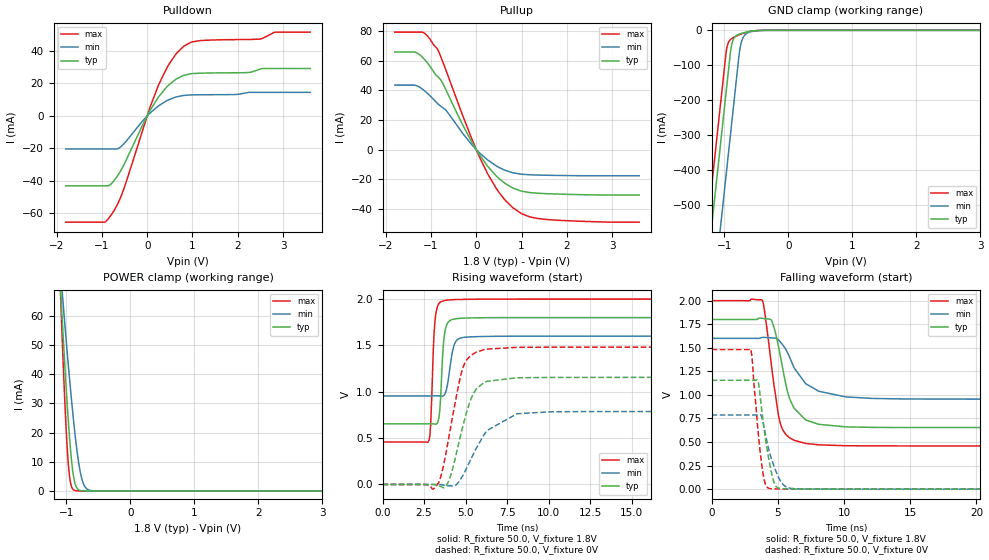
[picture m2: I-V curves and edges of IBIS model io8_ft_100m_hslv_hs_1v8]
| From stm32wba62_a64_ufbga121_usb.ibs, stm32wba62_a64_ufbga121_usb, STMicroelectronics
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[Model]   io8_ft_100m_hslv_hs_1v8
Model_type I/O
Polarity   Non-Inverting
Enable   Active-Low
| CAP_THRESHOLD on pad IOFT is "UDTCAPC" :
| Rising=30.0% of vddiom   Falling=70.0% of vddiom
| C_comp min and max val. don't necessarily correlate with the min and max pvt
| but are the smallest and greatest pad capacitance found.
| var   typ   min   max
C_comp   3.45872pF  3.43507pF  3.59281pF
|C_comp_pullup   2.05788pF  1.95427pF  2.20521pF
|C_comp_pulldown   1.40085pF  1.48081pF  1.38760pF
Vinl = 800.0mV
Vinh = 1.0V
Vmeas = 900.0mV   | Reference voltage for timing measurements
Cref  = 50.0pF   | Timing specification test load capacitance value
Rref  = 1.0MOhm   | Timing specification test load resistance value
Vref  = 990.0mV   | Timing specification test load voltage
[Model Spec]
| TIME_THRESHOLD on pin ZIV11 is "CMOS" :
| Rising=50.0% of vdd   Falling=50.0% of vdd
Vinl 702.50000mV 626.50000mV 788.50000mV
Vinh 1.09050V 959.50000mV 1.19650V
| variable   typ   min   max
[Temperature Range] 25.0 140.0 -40.0
| variable   typ   min   max
[Voltage Range] 1.8V 1.6V 2.0V
| variable   typ   min   max
[POWER Clamp Reference] 1.8V 1.6V 2.0V
| variable   typ   min   max
[GND Clamp Reference] 0V 0V 0V
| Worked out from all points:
|   slope of the pulldown table from 0 to 0.27 V, typ, clamps not added: 21.9 ohm
|   slope of the pullup table from 0 to 0.27 V, typ, clamps not added: 22.7 ohm
|   GND clamp passes 1 mA (typ) near -0.51 V on its own axis
|   POWER clamp passes 1 mA (typ) near -0.83 V on its own axis
|   rising waveform, R_fixture 50.0, V_fixture 1.8V: 20-80 % time 217ps typ, 343ps min, 202ps max; typ from 0.654 V to 1.8 V
|   falling waveform, R_fixture 50.0, V_fixture 1.8V: 20-80 % time 1.19ns typ, 1.89ns min, 886ps max; typ from 1.8 V to 0.654 V
|   rising waveform, R_fixture 50.0, V_fixture 0V: 20-80 % time 1.03ns typ, 1.75ns min, 947ps max; typ from 0 V to 1.16 V
|   falling waveform, R_fixture 50.0, V_fixture 0V: 20-80 % time 726ps typ, 952ps min, 588ps max; typ from 1.16 V to 0 V
[POWER Clamp]
-1.8V     396.4mA    285.5mA    556.9mA
-1.09V    69.42mA    75.17mA    67.14mA
-1.08V    65.31mA    72.42mA    61.23mA
-1.06V    57.23mA    66.98mA    49.77mA
-1.02V    41.75mA    56.3mA     28.91mA
-980mV    27.6mA     45.97mA    12.6mA
-940mV    15.59mA    36.11mA    3.485mA
-880mV    4.091mA    22.61mA    262.5uA
-820mV    594.6uA    11.56mA    16.39uA
-760mV    69.41uA    4.321mA    1.008uA
-630mV    611.2nA    197uA      2.478nA
3.6V      0A         0A         0A
[GND Clamp]
-1.8V     -1.583A    -1.82A     -1.468A
-1.43V    -953.9mA   -1.191A    -839.3mA
-1.24V    -630.9mA   -867.8mA   -516.3mA
-1.05V    -307.9mA   -544.8mA   -193.3mA
-980mV    -188.9mA   -425.8mA   -74.3mA
-950mV    -137.9mA   -374.8mA   -41.62mA
-890mV    -44.57mA   -272.8mA   -24.11mA
-800mV    -13.55mA   -119.8mA   -15.31mA
-760mV    -10.3mA    -56.67mA   -12.19mA
-720mV    -7.957mA   -26.08mA   -9.381mA
-540mV    -1.564mA   -2.435mA   -1.367mA
3.6V      1.279nA    269.1nA    528.1pA
| variable   typ   min   max
[Pullup Reference] 1.8V 1.6V 2.0V
| variable   typ   min   max
[Pulldown Reference] 0V 0V 0V
[Pullup]
-1.8V     66.02mA    43.62mA    79.48mA
-1.3V     65.22mA    42.98mA    79.48mA
-1.13V    60.52mA    39.44mA    78.38mA
-860mV    49.51mA    31.33mA    68.19mA
-760mV    45.99mA    28.84mA    60.97mA
-310mV    17.32mA    11.41mA    23.88mA
70mV      -3.436mA   -2.157mA   -4.962mA
440mV     -17.8mA    -11.01mA   -26.16mA
810mV     -26.07mA   -15.71mA   -39.4mA
1V        -28.15mA   -16.69mA   -43.34mA
1.37V     -29.57mA   -17.25mA   -46.68mA
3.6V      -30.74mA   -17.73mA   -49.13mA
[Pulldown]
-1.8V     -42.97mA   -20.34mA   -65.35mA
-940mV    -42.97mA   -20.34mA   -65.31mA
-780mV    -41.3mA    -20.34mA   -60.25mA
-530mV    -30.86mA   -17.55mA   -45.89mA
0V        -2fA       -570fA     -3.81fA
250mV     11.67mA    6.208mA    19.03mA
460mV     18.64mA    9.755mA    30.89mA
810mV     24.97mA    12.61mA    42.87mA
1.18V     26.28mA    13mA       46.33mA
2.49V     28.73mA    14.48mA    47.25mA
2.83V     29.16mA    14.48mA    51.53mA
3.6V      29.16mA    14.48mA    51.53mA
[Ramp]
dV/dt_r 693.11099mV/1.0245ns 472.15149mV/1.51156ns 888.79144mV/946.59581ps
dV/dt_f 687.69255mV/1.18433ns 386.84156mV/1.79429ns 924.86457mV/883.35799ps
R_load = 50.0
| Removed startup time: 0s 0s 0s  .
| Removed end time: 36.25ns.
[Rising Waveform]
R_fixture   = 50.0
V_fixture   = 1.8V
V_fixture_min = 1.6V
V_fixture_max = 2.0V
0s        653.8mV    955.3mV    458.6mV
2.8ns     653.9mV    955.4mV    476.4mV
2.9ns     654.2mV    955.4mV    646.7mV
3.05ns    654.3mV    955.6mV    1.413V
3.15ns    652.5mV    955.9mV    1.747V
3.45ns    801.9mV    955.3mV    1.963V
3.7ns     1.576V     961.4mV    1.982V
4.3ns     1.784V     1.496V     1.994V
4.95ns    1.794V     1.588V     1.997V
36.25ns   1.8V       1.6V       2V
| Removed startup time: 0s 0s 0s  .
| Removed end time: 99.25ns.
[Falling Waveform]
R_fixture   = 50.0
V_fixture   = 1.8V
V_fixture_min = 1.6V
V_fixture_max = 2.0V
0s        1.8V       1.6V       2V
3.85ns    1.812V     1.61V      1.997V
4.1ns     1.807V     1.609V     1.79V
4.55ns    1.782V     1.605V     1.281V
5.2ns     1.407V     1.56V      693.7mV
5.95ns    941.5mV    1.381V     540.2mV
7.1ns     734.3mV    1.12V      485.2mV
10.15ns   660.9mV    978.4mV    460.8mV
14.2ns    654.2mV    957.7mV    458.7mV
99.25ns   653.8mV    955.3mV    458.6mV
| Removed startup time: 0s 0s 0s  .
| Removed end time: 99.2ns.
[Rising Waveform]
R_fixture   = 50.0
V_fixture   = 0V
V_fixture_min = 0V
V_fixture_max = 0V
0s        4.616nV    149.8nV    3.36nV
3.3ns     -11mV      -64.4uV    -1.485mV
3.6ns     -29.18mV   -4.206mV   146.5mV
4ns       43.68mV    -14.62mV   513.9mV
4.85ns    636.5mV    101.4mV    1.263V
5.5ns     988.8mV    338.8mV    1.412V
6.3ns     1.113V     582.7mV    1.46V
8.1ns     1.151V     763.2mV    1.479V
10.15ns   1.155V     784.1mV    1.481V
99.2ns    1.155V     786.9mV    1.481V
| Removed startup time: 0s 0s 0s  .
| Removed end time: 36.25ns.
[Falling Waveform]
R_fixture   = 50.0
V_fixture   = 0V
V_fixture_min = 0V
V_fixture_max = 0V
0s        1.155V     786.9mV    1.481V
2.95ns    1.155V     787mV      1.485V
3.05ns    1.155V     787.1mV    1.403V
3.5ns     1.152V     788.7mV    631.9mV
3.8ns     825.6mV    758.2mV    249mV
4.05ns    548.6mV    596mV      60.83mV
4.35ns    298.8mV    404.3mV    8.598mV
4.85ns    32.45mV    193.9mV    2.677mV
5.95ns    2.427mV    8.508mV    1.118mV
36.25ns   56.59nV    570.2nV    10.4nV
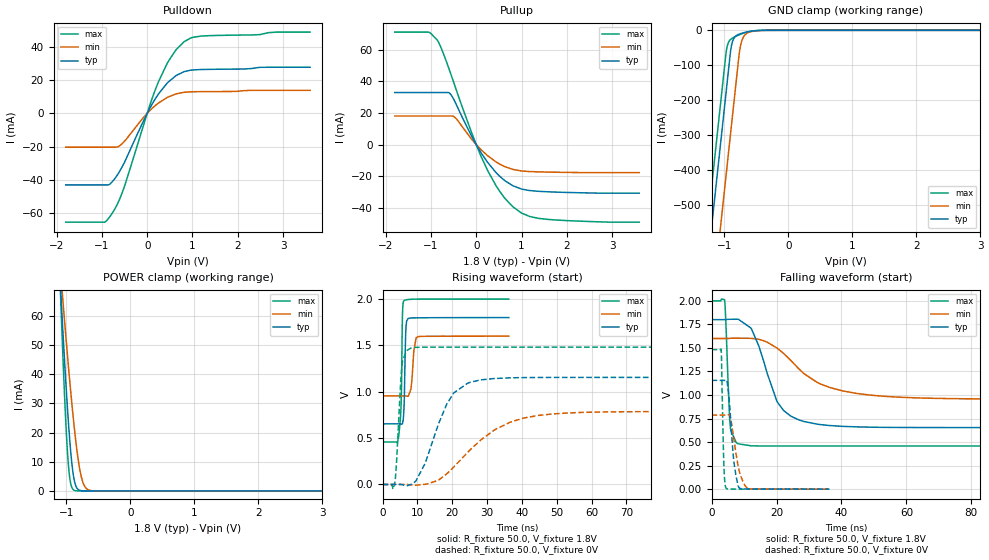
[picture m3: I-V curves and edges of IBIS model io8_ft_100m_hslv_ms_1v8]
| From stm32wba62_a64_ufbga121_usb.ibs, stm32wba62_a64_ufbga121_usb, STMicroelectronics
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[Model]   io8_ft_100m_hslv_ms_1v8
Model_type I/O
Polarity   Non-Inverting
Enable   Active-Low
| CAP_THRESHOLD on pad IOFT is "UDTCAPC" :
| Rising=30.0% of vddiom   Falling=70.0% of vddiom
| C_comp min and max val. don't necessarily correlate with the min and max pvt
| but are the smallest and greatest pad capacitance found.
| var   typ   min   max
C_comp   3.45864pF  3.43495pF  3.62425pF
|C_comp_pullup   2.05752pF  1.95381pF  2.23556pF
|C_comp_pulldown   1.40113pF  1.48114pF  1.38868pF
Vinl = 800.0mV
Vinh = 1.0V
Vmeas = 900.0mV   | Reference voltage for timing measurements
Cref  = 50.0pF   | Timing specification test load capacitance value
Rref  = 1.0MOhm   | Timing specification test load resistance value
Vref  = 990.0mV   | Timing specification test load voltage
[Model Spec]
| TIME_THRESHOLD on pin ZIV11 is "CMOS" :
| Rising=50.0% of vdd   Falling=50.0% of vdd
Vinl 702.50000mV 626.50000mV 788.50000mV
Vinh 1.09050V 959.50000mV 1.19650V
| variable   typ   min   max
[Temperature Range] 25.0 140.0 -40.0
| variable   typ   min   max
[Voltage Range] 1.8V 1.6V 2.0V
| variable   typ   min   max
[POWER Clamp Reference] 1.8V 1.6V 2.0V
| variable   typ   min   max
[GND Clamp Reference] 0V 0V 0V
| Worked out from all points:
|   slope of the pulldown table from 0 to 0.27 V, typ, clamps not added: 21.9 ohm
|   slope of the pullup table from 0 to 0.27 V, typ, clamps not added: 22.7 ohm
|   GND clamp passes 1 mA (typ) near -0.51 V on its own axis
|   POWER clamp passes 1 mA (typ) near -0.83 V on its own axis
|   rising waveform, R_fixture 50.0, V_fixture 1.8V: 20-80 % time 385ps typ, 810ps min, 429ps max; typ from 0.654 V to 1.8 V
|   falling waveform, R_fixture 50.0, V_fixture 1.8V: 20-80 % time 7.24ns typ, 14.9ns min, 1.05ns max; typ from 1.8 V to 0.654 V
|   rising waveform, R_fixture 50.0, V_fixture 0V: 20-80 % time 7.14ns typ, 14.7ns min, 1.26ns max; typ from 0 V to 1.16 V
|   falling waveform, R_fixture 50.0, V_fixture 0V: 20-80 % time 1.63ns typ, 2.37ns min, 590ps max; typ from 1.16 V to 0 V
[POWER Clamp]
-1.8V     396.4mA    285.5mA    556.9mA
-1.09V    69.42mA    75.17mA    67.14mA
-1.08V    65.31mA    72.42mA    61.23mA
-1.06V    57.23mA    66.98mA    49.77mA
-1.02V    41.75mA    56.3mA     28.91mA
-980mV    27.6mA     45.97mA    12.6mA
-940mV    15.59mA    36.11mA    3.485mA
-880mV    4.091mA    22.61mA    262.5uA
-820mV    594.6uA    11.56mA    16.39uA
-760mV    69.41uA    4.321mA    1.008uA
-630mV    611.3nA    197uA      2.478nA
3.6V      0A         0A         0A
[GND Clamp]
-1.8V     -1.583A    -1.82A     -1.468A
-1.43V    -953.9mA   -1.191A    -839.3mA
-1.24V    -630.9mA   -867.8mA   -516.3mA
-1.05V    -307.9mA   -544.8mA   -193.3mA
-980mV    -188.9mA   -425.8mA   -74.3mA
-950mV    -137.9mA   -374.8mA   -41.62mA
-890mV    -44.57mA   -272.8mA   -24.11mA
-800mV    -13.55mA   -119.8mA   -15.31mA
-760mV    -10.3mA    -56.67mA   -12.19mA
-720mV    -7.957mA   -26.08mA   -9.381mA
-540mV    -1.564mA   -2.435mA   -1.367mA
3.6V      1.279nA    269.1nA    528.1pA
| variable   typ   min   max
[Pullup Reference] 1.8V 1.6V 2.0V
| variable   typ   min   max
[Pulldown Reference] 0V 0V 0V
[Pullup]
-1.8V     33mA       18.15mA    71.29mA
-1.06V    33mA       18.15mA    71.26mA
-860mV    33mA       18.15mA    66.24mA
-560mV    31.64mA    18.15mA    44.58mA
-440mV    25.34mA    16.38mA    34.57mA
-120mV    6.338mA    4.065mA    8.965mA
110mV     -5.296mA   -3.32mA    -7.658mA
440mV     -17.8mA    -11.01mA   -26.16mA
810mV     -26.07mA   -15.71mA   -39.4mA
1V        -28.15mA   -16.69mA   -43.34mA
1.37V     -29.57mA   -17.25mA   -46.68mA
3.6V      -30.74mA   -17.73mA   -49.13mA
[Pulldown]
-1.8V     -42.97mA   -20.34mA   -65.35mA
-940mV    -42.97mA   -20.34mA   -65.31mA
-780mV    -41.3mA    -20.34mA   -60.25mA
-650mV    -36.58mA   -20.1mA    -53.93mA
-530mV    -30.86mA   -17.55mA   -45.89mA
0V        2.4fA      -230fA     0A
250mV     11.67mA    6.208mA    19.03mA
460mV     18.64mA    9.755mA    30.89mA
630mV     22.5mA     11.58mA    37.88mA
810mV     24.97mA    12.61mA    42.87mA
1.18V     26.28mA    13mA       46.33mA
3.6V      27.66mA    13.8mA     48.75mA
[Ramp]
dV/dt_r 693.10101mV/7.01092ns 472.10736mV/14.47133ns 888.7928mV/1.25662ns
dV/dt_f 687.69291mV/7.00172ns 386.8437mV/14.79899ns 924.86462mV/1.05074ns
R_load = 50.0
| Removed startup time: 0s 0s 0s  .
| Removed end time: 36.25ns.
[Rising Waveform]
R_fixture   = 50.0
V_fixture   = 1.8V
V_fixture_min = 1.6V
V_fixture_max = 2.0V
0s        653.8mV    955.3mV    458.6mV
4.65ns    653.9mV    955.3mV    522.8mV
5.3ns     651.8mV    955.3mV    838.2mV
5.7ns     657.4mV    955.3mV    1.8V
6.1ns     781.3mV    955.3mV    1.98V
6.7ns     1.674V     954.6mV    1.991V
7.35ns    1.79V      951.2mV    1.995V
8.15ns    1.796V     1.029V     1.997V
9.65ns    1.797V     1.584V     1.999V
36.25ns   1.8V       1.6V       2V
| Removed startup time: 0s 0s 0s  .
| Removed end time: 199.25ns.
[Falling Waveform]
R_fixture   = 50.0
V_fixture   = 1.8V
V_fixture_min = 1.6V
V_fixture_max = 2.0V
0s        1.8V       1.6V       2V
4.05ns    1.8V       1.6V       2.003V
5.7ns     1.804V     1.602V     690.4mV
8.2ns     1.805V     1.603V     481.4mV
12.2ns    1.709V     1.602V     460.2mV
20.05ns   940.3mV    1.501V     458.6mV
22.2ns    834.7mV    1.441V     458.6mV
32.55ns   689.9mV    1.133V     458.6mV
65.1ns    654.5mV    967.3mV    458.6mV
199.3ns   653.8mV    955.3mV    458.6mV
| Removed startup time: 0s 0s 0s  .
| Removed end time: 199.2ns.
[Rising Waveform]
R_fixture   = 50.0
V_fixture   = 0V
V_fixture_min = 0V
V_fixture_max = 0V
0s        4.612nV    149.7nV    3.102nV
3.45ns    3.66uV     3.237uV    7.375mV
3.95ns    1.413uV    2.741uV    200.7mV
5.6ns     -1.633mV   101.6nV    1.29V
8.15ns    52.07uV    -4.203mV   1.472V
12.2ns    225.7mV    1.966mV    1.481V
20.35ns   982.5mV    184.4mV    1.481V
28.45ns   1.129V     487mV      1.481V
52.85ns   1.155V     770.7mV    1.481V
199.2ns   1.155V     786.8mV    1.481V
| Removed startup time: 0s 0s 0s  .
| Removed end time: 36.25ns.
[Falling Waveform]
R_fixture   = 50.0
V_fixture   = 0V
V_fixture_min = 0V
V_fixture_max = 0V
0s        1.155V     786.9mV    1.481V
2.95ns    1.155V     786.9mV    1.485V
3.8ns     1.155V     786.9mV    251.4mV
4.05ns    1.155V     786.9mV    87.48mV
4.45ns    1.157V     786.9mV    11.74mV
5.2ns     1.03V      789.1mV    2.24mV
6.9ns     283.3mV    522.1mV    777.8uV
8.45ns    15.14mV    201.1mV    318.5uV
11.85ns   1.5mV      2.949mV    50.23uV
36.25ns   41.83uV    151.8uV    18.8nV
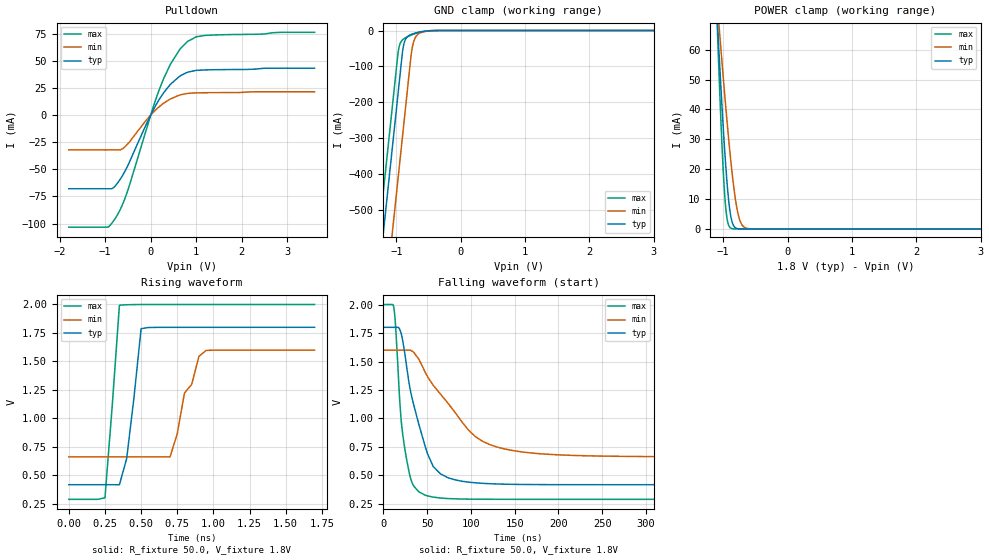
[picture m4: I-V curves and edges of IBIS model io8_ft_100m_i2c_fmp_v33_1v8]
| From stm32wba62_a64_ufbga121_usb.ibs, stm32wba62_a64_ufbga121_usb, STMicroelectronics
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[Model]   io8_ft_100m_i2c_fmp_v33_1v8
Model_type I/O_open_drain
Polarity   Non-Inverting
Enable   Active-Low
| CAP_THRESHOLD on pad IOFT is "UDTCAPC" :
| Rising=30.0% of vddiom   Falling=70.0% of vddiom
| C_comp min and max val. don't necessarily correlate with the min and max pvt
| but are the smallest and greatest pad capacitance found.
| var   typ   min   max
C_comp   3.34864pF  3.31909pF  3.48425pF
|C_comp_pulldown   3.34864pF  3.31909pF  3.48425pF
Vinl = 800.0mV
Vinh = 1.0V
Vmeas = 900.0mV   | Reference voltage for timing measurements
Cref  = 50.0pF   | Timing specification test load capacitance value
Rref  = 1.0MOhm   | Timing specification test load resistance value
Vref  = 990.0mV   | Timing specification test load voltage
[Model Spec]
| TIME_THRESHOLD on pin ZII2CV11 is "CMOS" :
| Rising=50.0% of vdd   Falling=50.0% of vdd
Vinl 697.50000mV 620.50000mV 783.50000mV
Vinh 1.08850V 957.50000mV 1.19550V
| variable   typ   min   max
[Temperature Range] 25.0 140.0 -40.0
| variable   typ   min   max
[Voltage Range] 1.8V 1.6V 2.0V
| variable   typ   min   max
[POWER Clamp Reference] 1.8V 1.6V 2.0V
| variable   typ   min   max
[GND Clamp Reference] 0V 0V 0V
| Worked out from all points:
|   slope of the pulldown table from 0 to 0.27 V, typ, clamps not added: 13.7 ohm
|   GND clamp passes 1 mA (typ) near -0.51 V on its own axis
|   POWER clamp passes 1 mA (typ) near -0.83 V on its own axis
|   rising waveform, R_fixture 50.0, V_fixture 1.8V: 20-80 % time 74ps typ, 127ps min, 60.6ps max; typ from 0.419 V to 1.8 V
|   falling waveform, R_fixture 50.0, V_fixture 1.8V: 20-80 % time 25ns typ, 56.4ns min, 11.6ns max; typ from 1.8 V to 0.419 V
[POWER Clamp]
-1.8V     396.4mA    285.5mA    556.9mA
-1.09V    69.42mA    75.17mA    67.14mA
-1.08V    65.31mA    72.42mA    61.23mA
-1.06V    57.23mA    66.98mA    49.77mA
-1.02V    41.75mA    56.3mA     28.91mA
-980mV    27.6mA     45.97mA    12.6mA
-940mV    15.59mA    36.11mA    3.485mA
-880mV    4.091mA    22.61mA    262.5uA
-820mV    594.6uA    11.56mA    16.39uA
-760mV    69.41uA    4.321mA    1.008uA
-630mV    611.2nA    197uA      2.486nA
3.6V      0A         0A         0A
[GND Clamp]
-1.8V     -1.583A    -1.82A     -1.468A
-1.43V    -953.9mA   -1.191A    -839.3mA
-1.24V    -630.9mA   -867.8mA   -516.3mA
-1.05V    -307.9mA   -544.8mA   -193.3mA
-980mV    -188.9mA   -425.8mA   -74.3mA
-950mV    -137.9mA   -374.8mA   -41.62mA
-890mV    -44.57mA   -272.8mA   -24.11mA
-800mV    -13.55mA   -119.8mA   -15.31mA
-760mV    -10.3mA    -56.67mA   -12.19mA
-720mV    -7.957mA   -26.08mA   -9.381mA
-540mV    -1.564mA   -2.435mA   -1.367mA
3.6V      1.281nA    268.1nA    531.2pA
| variable   typ   min   max
[Pullup Reference] 1.8V 1.6V 2.0V
| variable   typ   min   max
[Pulldown Reference] 0V 0V 0V
[Pulldown]
-1.8V     -67.91mA   -32.13mA   -103.3mA
-940mV    -67.91mA   -32.13mA   -103.2mA
-780mV    -65.26mA   -32.13mA   -95.24mA
-650mV    -57.81mA   -31.76mA   -85.25mA
-530mV    -48.77mA   -27.72mA   -72.55mA
0V        1fA        -20fA      -1.8fA
250mV     18.45mA    9.809mA    30.09mA
440mV     28.58mA    14.98mA    47.3mA
630mV     35.56mA    18.31mA    59.9mA
810mV     39.48mA    19.92mA    67.8mA
1.18V     41.55mA    20.55mA    73.29mA
3.6V      43.15mA    21.44mA    76.19mA
[Ramp]
dV/dt_r 828.62853mV/1.35705ns 561.62363mV/2.54413ns 1.02558V/770.99655ps
dV/dt_f 828.65502mV/24.91356ns 561.51224mV/56.08077ns 1.02559V/11.58574ns
R_load = 50.0
| Removed startup time: 0s 0s 0s  .
| Removed end time: 1.7ns.
[Rising Waveform]
R_fixture   = 50.0
V_fixture   = 1.8V
V_fixture_min = 1.6V
V_fixture_max = 2.0V
0s        418.9mV    663.9mV    290.7mV
250ps     418.9mV    663.9mV    303.9mV
350ps     418mV      663.9mV    1.994V
400ps     647.5mV    663.9mV    1.998V
500ps     1.788V     663.9mV    2V
700ps     1.8V       662.7mV    2V
750ps     1.8V       865.4mV    2V
800ps     1.8V       1.223V     2V
950ps     1.8V       1.597V     2V
1.7ns     1.8V       1.6V       2V
| Removed startup time: 0s 0s 0s  .
| Removed end time: 398.4ns.
[Falling Waveform]
R_fixture   = 50.0
V_fixture   = 1.8V
V_fixture_min = 1.6V
V_fixture_max = 2.0V
0s        1.8V       1.6V       2V
11.85ns   1.8V       1.6V       1.975V
22.1ns    1.683V     1.6V       859.3mV
31.35ns   1.228V     1.597V     467.6mV
40.65ns   944.5mV    1.518V     355.8mV
50.5ns    689.4mV    1.366V     320.8mV
65.05ns   515.3mV    1.216V     302.3mV
97.6ns    441.2mV    895.3mV    292.4mV
130.1ns   425.4mV    749mV      291mV
398.4ns   418.9mV    664.1mV    290.7mV
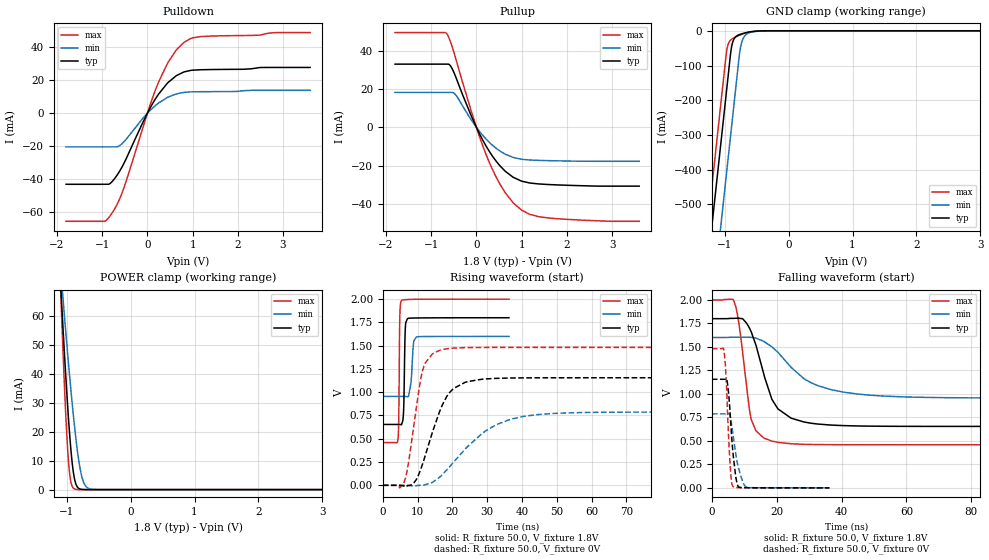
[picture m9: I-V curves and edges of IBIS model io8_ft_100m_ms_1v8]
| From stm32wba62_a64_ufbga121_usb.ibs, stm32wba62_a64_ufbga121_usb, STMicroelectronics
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[Model]   io8_ft_100m_ms_1v8
Model_type I/O
Polarity   Non-Inverting
Enable   Active-Low
| CAP_THRESHOLD on pad IOFT is "UDTCAPC" :
| Rising=30.0% of vddiom   Falling=70.0% of vddiom
| C_comp min and max val. don't necessarily correlate with the min and max pvt
| but are the smallest and greatest pad capacitance found.
| var   typ   min   max
C_comp   3.36302pF  3.33592pF  3.49657pF
|C_comp_pullup   1.98082pF  1.87509pF  2.12867pF
|C_comp_pulldown   1.38220pF  1.46083pF  1.36790pF
Vinl = 800.0mV
Vinh = 1.0V
Vmeas = 900.0mV   | Reference voltage for timing measurements
Cref  = 50.0pF   | Timing specification test load capacitance value
Rref  = 1.0MOhm   | Timing specification test load resistance value
Vref  = 990.0mV   | Timing specification test load voltage
[Model Spec]
| TIME_THRESHOLD on pin ZIV11 is "CMOS" :
| Rising=50.0% of vdd   Falling=50.0% of vdd
Vinl 702.50000mV 626.50000mV 788.50000mV
Vinh 1.09050V 959.50000mV 1.19650V
| variable   typ   min   max
[Temperature Range] 25.0 140.0 -40.0
| variable   typ   min   max
[Voltage Range] 1.8V 1.6V 2.0V
| variable   typ   min   max
[POWER Clamp Reference] 1.8V 1.6V 2.0V
| variable   typ   min   max
[GND Clamp Reference] 0V 0V 0V
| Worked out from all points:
|   slope of the pulldown table from 0 to 0.27 V, typ, clamps not added: 21.9 ohm
|   slope of the pullup table from 0 to 0.27 V, typ, clamps not added: 22.5 ohm
|   GND clamp passes 1 mA (typ) near -0.51 V on its own axis
|   POWER clamp passes 1 mA (typ) near -0.83 V on its own axis
|   rising waveform, R_fixture 50.0, V_fixture 1.8V: 20-80 % time 320ps typ, 666ps min, 236ps max; typ from 0.654 V to 1.8 V
|   falling waveform, R_fixture 50.0, V_fixture 1.8V: 20-80 % time 6.53ns typ, 13.6ns min, 3.34ns max; typ from 1.8 V to 0.654 V
|   rising waveform, R_fixture 50.0, V_fixture 0V: 20-80 % time 6.51ns typ, 13.4ns min, 3.54ns max; typ from 0 V to 1.16 V
|   falling waveform, R_fixture 50.0, V_fixture 0V: 20-80 % time 1.61ns typ, 2.38ns min, 1.18ns max; typ from 1.16 V to 0 V
[POWER Clamp]
-1.8V     396.4mA    285.5mA    556.9mA
-1.09V    69.42mA    75.17mA    67.14mA
-1.08V    65.31mA    72.42mA    61.23mA
-1.06V    57.23mA    66.98mA    49.77mA
-1.02V    41.75mA    56.3mA     28.91mA
-980mV    27.6mA     45.97mA    12.6mA
-940mV    15.59mA    36.11mA    3.485mA
-880mV    4.091mA    22.61mA    262.5uA
-820mV    594.6uA    11.56mA    16.39uA
-760mV    69.41uA    4.321mA    1.008uA
-630mV    611.2nA    197uA      2.486nA
3.6V      0A         0A         0A
[GND Clamp]
-1.8V     -1.583A    -1.82A     -1.468A
-1.43V    -953.9mA   -1.191A    -839.3mA
-1.24V    -630.9mA   -867.8mA   -516.3mA
-1.05V    -307.9mA   -544.8mA   -193.3mA
-980mV    -188.9mA   -425.8mA   -74.3mA
-950mV    -137.9mA   -374.8mA   -41.62mA
-890mV    -44.57mA   -272.8mA   -24.11mA
-800mV    -13.55mA   -119.8mA   -15.31mA
-760mV    -10.3mA    -56.67mA   -12.19mA
-720mV    -7.957mA   -26.08mA   -9.381mA
-540mV    -1.564mA   -2.435mA   -1.367mA
3.6V      1.281nA    268.1nA    531.2pA
| variable   typ   min   max
[Pullup Reference] 1.8V 1.6V 2.0V
| variable   typ   min   max
[Pulldown Reference] 0V 0V 0V
[Pullup]
-1.8V     33.1mA     18.3mA     49.62mA
-650mV    33.1mA     18.3mA     48.8mA
-570mV    32.05mA    18.3mA     44.54mA
-460mV    26.55mA    17.03mA    36.18mA
0V        593fA      222.5pA    3.42fA
280mV     -12.36mA   -7.702mA   -18.01mA
630mV     -22.78mA   -13.92mA   -33.91mA
810mV     -26.07mA   -15.71mA   -39.4mA
1V        -28.15mA   -16.69mA   -43.34mA
1.18V     -29.09mA   -17.06mA   -45.52mA
1.6V      -29.9mA    -17.4mA    -47.4mA
3.6V      -30.74mA   -17.73mA   -49.13mA
[Pulldown]
-1.8V     -42.97mA   -20.34mA   -65.35mA
-940mV    -42.97mA   -20.34mA   -65.31mA
-780mV    -41.3mA    -20.34mA   -60.25mA
-650mV    -36.58mA   -20.1mA    -53.93mA
-530mV    -30.86mA   -17.55mA   -45.89mA
0V        -1.6fA     0A         0A
250mV     11.67mA    6.208mA    19.03mA
460mV     18.64mA    9.755mA    30.89mA
630mV     22.5mA     11.58mA    37.88mA
810mV     24.97mA    12.61mA    42.87mA
1.18V     26.28mA    13mA       46.33mA
3.6V      27.68mA    13.83mA    48.76mA
[Ramp]
dV/dt_r 693.10628mV/6.46288ns 472.12859mV/13.31506ns 888.79178mV/3.53703ns
dV/dt_f 687.69291mV/6.33324ns 386.84616mV/13.42398ns 924.86465mV/3.34134ns
R_load = 50.0
| Removed startup time: 0s 0s 0s  .
| Removed end time: 36.25ns.
[Rising Waveform]
R_fixture   = 50.0
V_fixture   = 1.8V
V_fixture_min = 1.6V
V_fixture_max = 2.0V
0s        653.8mV    955.3mV    458.6mV
4.3ns     653.9mV    955.3mV    481.8mV
4.55ns    653.9mV    955.3mV    667.9mV
4.9ns     653.6mV    955.3mV    1.838V
5.35ns    650.2mV    955.3mV    1.985V
6ns       836.9mV    955.3mV    1.993V
6.5ns     1.712V     954.7mV    1.994V
7.1ns     1.791V     951.2mV    1.996V
9.65ns    1.797V     1.594V     1.998V
36.25ns   1.8V       1.6V       2V
| Removed startup time: 0s 0s 0s  .
| Removed end time: 199.25ns.
[Falling Waveform]
R_fixture   = 50.0
V_fixture   = 1.8V
V_fixture_min = 1.6V
V_fixture_max = 2.0V
0s        1.8V       1.6V       2V
6.75ns    1.803V     1.603V     1.993V
8.35ns    1.804V     1.602V     1.745V
12.2ns    1.653V     1.601V     721.7mV
13.6ns    1.518V     1.593V     606.6mV
18.5ns    942.5mV    1.5V       497.5mV
24.4ns    742.3mV    1.284V     469.2mV
30.65ns   687.3mV    1.117V     461.5mV
48.8ns    656.6mV    985.9mV    458.6mV
199.3ns   653.8mV    955.3mV    458.6mV
| Removed startup time: 0s 0s 0s  .
| Removed end time: 199.2ns.
[Rising Waveform]
R_fixture   = 50.0
V_fixture   = 0V
V_fixture_min = 0V
V_fixture_max = 0V
0s        4.66nV     149.2nV    3.397nV
6ns       -7.351mV   13.22uV    21.83mV
7.2ns     -3.754mV   -706.2uV   204.3mV
8.95ns    28.25mV    -10.05mV   653.6mV
11.45ns   232.8mV    1.899mV    1.236V
17.1ns    863.4mV    114.8mV    1.458V
20.35ns   1.041V     249.4mV    1.474V
29.7ns    1.143V     587.7mV    1.481V
44.75ns   1.155V     760.5mV    1.481V
199.2ns   1.155V     786.9mV    1.481V
| Removed startup time: 0s 0s 0s  .
| Removed end time: 36.25ns.
[Falling Waveform]
R_fixture   = 50.0
V_fixture   = 0V
V_fixture_min = 0V
V_fixture_max = 0V
0s        1.155V     786.9mV    1.481V
3.7ns     1.155V     786.9mV    1.461V
4.25ns    1.155V     786.9mV    1.258V
4.9ns     1.087V     787mV      741.7mV
5.75ns    731.2mV    742.4mV    181.1mV
6.05ns    572.3mV    680.9mV    67.91mV
6.4ns     412.7mV    597.5mV    19.68mV
7.8ns     38.95mV    274mV      3.09mV
10.35ns   2.119mV    12.81mV    775.3uV
36.25ns   30.42uV    125.9uV    3.735uV
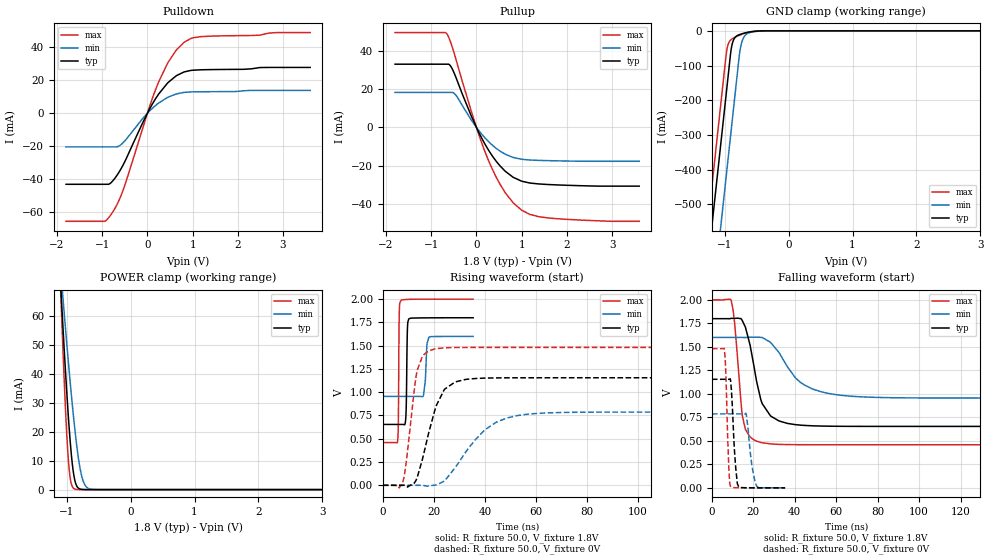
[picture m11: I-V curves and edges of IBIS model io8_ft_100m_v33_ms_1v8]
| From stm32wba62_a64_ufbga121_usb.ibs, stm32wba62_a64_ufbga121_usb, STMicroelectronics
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[Model]   io8_ft_100m_v33_ms_1v8
Model_type I/O
Polarity   Non-Inverting
Enable   Active-Low
| CAP_THRESHOLD on pad IOFT is "UDTCAPC" :
| Rising=30.0% of vddiom   Falling=70.0% of vddiom
| C_comp min and max val. don't necessarily correlate with the min and max pvt
| but are the smallest and greatest pad capacitance found.
| var   typ   min   max
C_comp   3.44267pF  3.41636pF  3.57935pF
|C_comp_pullup   2.04610pF  1.94135pF  2.19277pF
|C_comp_pulldown   1.39657pF  1.47502pF  1.38658pF
Vinl = 800.0mV
Vinh = 1.0V
Vmeas = 900.0mV   | Reference voltage for timing measurements
Cref  = 50.0pF   | Timing specification test load capacitance value
Rref  = 1.0MOhm   | Timing specification test load resistance value
Vref  = 990.0mV   | Timing specification test load voltage
[Model Spec]
| TIME_THRESHOLD on pin ZIV33M is "CMOS" :
| Rising=50.0% of vddiom   Falling=50.0% of vddiom
Vinl 697.50000mV 620.50000mV 783.50000mV
Vinh 1.08850V 957.50000mV 1.19550V
| variable   typ   min   max
[Temperature Range] 25.0 140.0 -40.0
| variable   typ   min   max
[Voltage Range] 1.8V 1.6V 2.0V
| variable   typ   min   max
[POWER Clamp Reference] 1.8V 1.6V 2.0V
| variable   typ   min   max
[GND Clamp Reference] 0V 0V 0V
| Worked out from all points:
|   slope of the pulldown table from 0 to 0.27 V, typ, clamps not added: 21.9 ohm
|   slope of the pullup table from 0 to 0.27 V, typ, clamps not added: 22.5 ohm
|   GND clamp passes 1 mA (typ) near -0.51 V on its own axis
|   POWER clamp passes 1 mA (typ) near -0.83 V on its own axis
|   rising waveform, R_fixture 50.0, V_fixture 1.8V: 20-80 % time 333ps typ, 735ps min, 241ps max; typ from 0.654 V to 1.8 V
|   falling waveform, R_fixture 50.0, V_fixture 1.8V: 20-80 % time 6.85ns typ, 14.4ns min, 3.5ns max; typ from 1.8 V to 0.654 V
|   rising waveform, R_fixture 50.0, V_fixture 0V: 20-80 % time 7.17ns typ, 14.4ns min, 3.76ns max; typ from 0 V to 1.16 V
|   falling waveform, R_fixture 50.0, V_fixture 0V: 20-80 % time 1.72ns typ, 2.52ns min, 1.25ns max; typ from 1.16 V to 0 V
[POWER Clamp]
-1.8V     396.4mA    285.5mA    556.9mA
-1.09V    69.42mA    75.17mA    67.14mA
-1.08V    65.31mA    72.42mA    61.23mA
-1.06V    57.23mA    66.98mA    49.77mA
-1.02V    41.75mA    56.3mA     28.91mA
-980mV    27.6mA     45.97mA    12.6mA
-940mV    15.59mA    36.11mA    3.485mA
-880mV    4.091mA    22.61mA    262.5uA
-820mV    594.6uA    11.56mA    16.39uA
-760mV    69.41uA    4.321mA    1.008uA
-630mV    611.2nA    197uA      2.486nA
3.6V      0A         0A         0A
[GND Clamp]
-1.8V     -1.583A    -1.82A     -1.468A
-1.43V    -953.9mA   -1.191A    -839.3mA
-1.24V    -630.9mA   -867.8mA   -516.3mA
-1.05V    -307.9mA   -544.8mA   -193.3mA
-980mV    -188.9mA   -425.8mA   -74.3mA
-950mV    -137.9mA   -374.8mA   -41.62mA
-890mV    -44.57mA   -272.8mA   -24.11mA
-800mV    -13.55mA   -119.8mA   -15.31mA
-760mV    -10.3mA    -56.67mA   -12.19mA
-720mV    -7.957mA   -26.08mA   -9.381mA
-540mV    -1.564mA   -2.435mA   -1.367mA
3.6V      1.281nA    268nA      531.2pA
| variable   typ   min   max
[Pullup Reference] 1.8V 1.6V 2.0V
| variable   typ   min   max
[Pulldown Reference] 0V 0V 0V
[Pullup]
-1.8V     33.11mA    18.3mA     49.64mA
-650mV    33.11mA    18.3mA     48.82mA
-570mV    32.06mA    18.3mA     44.54mA
-460mV    26.56mA    17.03mA    36.18mA
0V        593fA      222.5pA    3.42fA
280mV     -12.36mA   -7.702mA   -18.01mA
630mV     -22.78mA   -13.92mA   -33.91mA
810mV     -26.07mA   -15.71mA   -39.4mA
1V        -28.15mA   -16.69mA   -43.34mA
1.18V     -29.09mA   -17.06mA   -45.52mA
1.6V      -29.9mA    -17.4mA    -47.4mA
3.6V      -30.74mA   -17.73mA   -49.13mA
[Pulldown]
-1.8V     -42.97mA   -20.34mA   -65.35mA
-940mV    -42.97mA   -20.34mA   -65.31mA
-780mV    -41.3mA    -20.34mA   -60.25mA
-650mV    -36.58mA   -20.1mA    -53.93mA
-530mV    -30.86mA   -17.55mA   -45.89mA
0V        1fA        10fA       -3.6fA
250mV     11.67mA    6.208mA    19.03mA
460mV     18.64mA    9.755mA    30.89mA
630mV     22.5mA     11.58mA    37.88mA
810mV     24.97mA    12.61mA    42.87mA
1.18V     26.28mA    13mA       46.33mA
3.6V      27.7mA     13.84mA    48.79mA
[Ramp]
dV/dt_r 693.1053mV/6.84837ns 472.12267mV/14.08807ns 888.79146mV/3.75283ns
dV/dt_f 687.69291mV/6.60705ns 386.84608mV/14.00698ns 924.86464mV/3.48745ns
R_load = 50.0
| Removed startup time: 0s 0s 0s  .
| Removed end time: 35.4ns.
[Rising Waveform]
R_fixture   = 50.0
V_fixture   = 1.8V
V_fixture_min = 1.6V
V_fixture_max = 2.0V
0s        653.8mV    955.3mV    458.6mV
5.8ns     653.8mV    955.3mV    479.6mV
6.1ns     653.8mV    955.3mV    739.5mV
6.45ns    653.8mV    955.3mV    1.86V
7.25ns    653.9mV    955.3mV    1.991V
9ns       728.6mV    955.3mV    1.996V
10.15ns   1.787V     955.3mV    1.998V
15.9ns    1.798V     958.1mV    2V
18.1ns    1.799V     1.593V     2V
35.4ns    1.8V       1.599V     2V
| Removed startup time: 0s 0s 0s  .
| Removed end time: 198.4ns.
[Falling Waveform]
R_fixture   = 50.0
V_fixture   = 1.8V
V_fixture_min = 1.6V
V_fixture_max = 2.0V
0s        1.8V       1.6V       2V
9.3ns     1.803V     1.6V       1.995V
11.15ns   1.803V     1.6V       1.71V
14.7ns    1.779V     1.6V       769.3mV
21.55ns   1.137V     1.603V     497.1mV
24.3ns    895.4mV    1.6V       479.6mV
28.35ns   764.3mV    1.547V     467.7mV
40.5ns    672.1mV    1.166V     459.5mV
56.7ns    656.1mV    1.003V     458.6mV
198.4ns   653.8mV    955.3mV    458.6mV
| Removed startup time: 0s 0s 0s  .
| Removed end time: 198.35ns.
[Rising Waveform]
R_fixture   = 50.0
V_fixture   = 0V
V_fixture_min = 0V
V_fixture_max = 0V
0s        4.761nV    149.3nV    3.5nV
7.65ns    6.516uV    147.9nV    18.91mV
9ns       -5.223mV   145.7nV    212.8mV
13.45ns   81.81mV    1.034uV    1.234V
20.25ns   793.6mV    1.452mV    1.464V
24.05ns   1.027V     44.28mV    1.477V
28.35ns   1.11V      188.5mV    1.48V
40.5ns    1.152V     605.3mV    1.481V
52.65ns   1.155V     748.7mV    1.481V
198.3ns   1.155V     786.9mV    1.481V
| Removed startup time: 0s 0s 0s  .
| Removed end time: 35.35ns.
[Falling Waveform]
R_fixture   = 50.0
V_fixture   = 0V
V_fixture_min = 0V
V_fixture_max = 0V
0s        1.155V     786.9mV    1.481V
6ns       1.155V     786.9mV    1.478V
6.65ns    1.155V     786.9mV    1.269V
8.2ns     1.155V     786.9mV    207.2mV
9ns       1.147V     786.9mV    16.53mV
11.25ns   288.8mV    786.9mV    1.78mV
13ns      7.048mV    786.9mV    796.2uV
16.6ns    1.3mV      784.1mV    359.2uV
21.65ns   461.7uV    16.53mV    138.6uV
35.35ns   80.53uV    458.6uV    9.617uV
